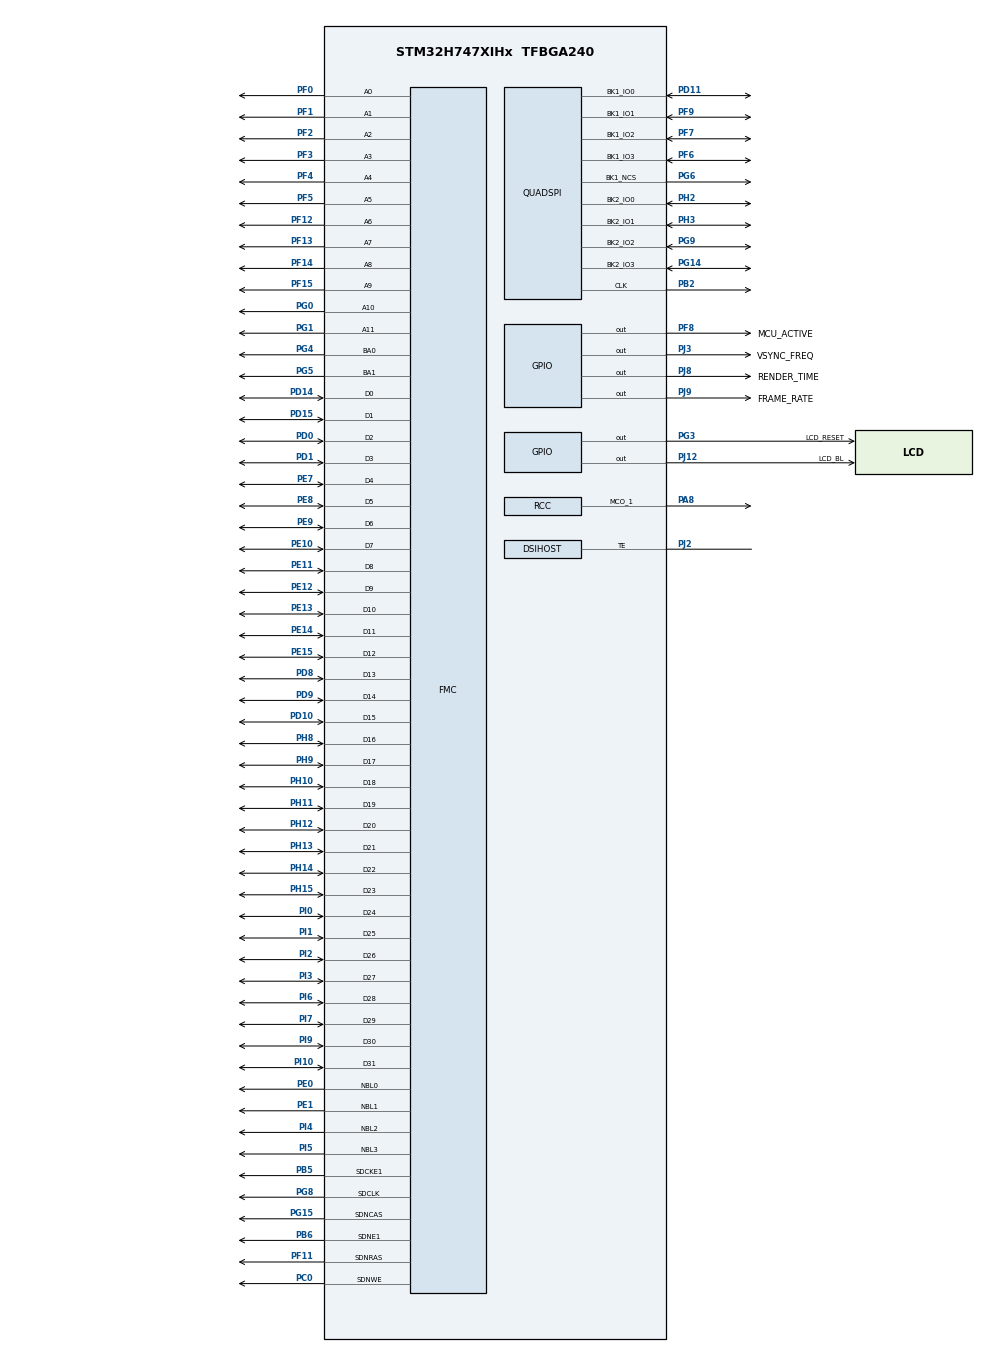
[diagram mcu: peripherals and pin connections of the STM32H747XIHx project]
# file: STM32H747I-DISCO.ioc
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CORTEX_M7.AccessPermission-Cortex_Memory_Protection_Unit_Region0_Settings=MPU_REGION_FULL_ACCESS
CORTEX_M7.AccessPermission-Cortex_Memory_Protection_Unit_Region1_Settings=MPU_REGION_FULL_ACCESS
CORTEX_M7.AccessPermission-Cortex_Memory_Protection_Unit_Region2_Settings=MPU_REGION_FULL_ACCESS
CORTEX_M7.AccessPermission-Cortex_Memory_Protection_Unit_Region3_Settings=MPU_REGION_FULL_ACCESS
CORTEX_M7.AccessPermission-Cortex_Memory_Protection_Unit_Region4_Settings=MPU_REGION_FULL_ACCESS
CORTEX_M7.AccessPermission-Cortex_Memory_Protection_Unit_Region5_Settings=MPU_REGION_FULL_ACCESS
CORTEX_M7.BaseAddress-Cortex_Memory_Protection_Unit_Region0_Settings=0x90000000
CORTEX_M7.BaseAddress-Cortex_Memory_Protection_Unit_Region1_Settings=0x90000000
CORTEX_M7.BaseAddress-Cortex_Memory_Protection_Unit_Region2_Settings=0xD0000000
CORTEX_M7.BaseAddress-Cortex_Memory_Protection_Unit_Region3_Settings=0x24000000
CORTEX_M7.BaseAddress-Cortex_Memory_Protection_Unit_Region4_Settings=0x10000000
CORTEX_M7.BaseAddress-Cortex_Memory_Protection_Unit_Region5_Settings=0x10040000
CORTEX_M7.CPU_DCache=Enabled
CORTEX_M7.CPU_ICache=Enabled
CORTEX_M7.DisableExec-Cortex_Memory_Protection_Unit_Region0_Settings=MPU_INSTRUCTION_ACCESS_DISABLE
CORTEX_M7.DisableExec-Cortex_Memory_Protection_Unit_Region1_Settings=MPU_INSTRUCTION_ACCESS_DISABLE
CORTEX_M7.DisableExec-Cortex_Memory_Protection_Unit_Region2_Settings=MPU_INSTRUCTION_ACCESS_DISABLE
CORTEX_M7.DisableExec-Cortex_Memory_Protection_Unit_Region3_Settings=MPU_INSTRUCTION_ACCESS_ENABLE
CORTEX_M7.DisableExec-Cortex_Memory_Protection_Unit_Region5_Settings=MPU_INSTRUCTION_ACCESS_DISABLE
CORTEX_M7.Enable-Cortex_Memory_Protection_Unit_Region0_Settings=MPU_REGION_ENABLE
CORTEX_M7.Enable-Cortex_Memory_Protection_Unit_Region1_Settings=MPU_REGION_ENABLE
CORTEX_M7.Enable-Cortex_Memory_Protection_Unit_Region2_Settings=MPU_REGION_ENABLE
CORTEX_M7.Enable-Cortex_Memory_Protection_Unit_Region3_Settings=MPU_REGION_ENABLE
CORTEX_M7.Enable-Cortex_Memory_Protection_Unit_Region4_Settings=MPU_REGION_ENABLE
CORTEX_M7.Enable-Cortex_Memory_Protection_Unit_Region5_Settings=MPU_REGION_ENABLE
CORTEX_M7.IsCacheable-Cortex_Memory_Protection_Unit_Region2_Settings=MPU_ACCESS_CACHEABLE
CORTEX_M7.IsCacheable-Cortex_Memory_Protection_Unit_Region3_Settings=MPU_ACCESS_CACHEABLE
CORTEX_M7.IsCacheable-Cortex_Memory_Protection_Unit_Region4_Settings=MPU_ACCESS_CACHEABLE
CORTEX_M7.IsCacheable-Cortex_Memory_Protection_Unit_Region5_Settings=MPU_ACCESS_CACHEABLE
CORTEX_M7.MPU_Control=MPU_PRIVILEGED_DEFAULT
CORTEX_M7.Size-Cortex_Memory_Protection_Unit_Region0_Settings=MPU_REGION_SIZE_256MB
CORTEX_M7.Size-Cortex_Memory_Protection_Unit_Region1_Settings=MPU_REGION_SIZE_128MB
CORTEX_M7.Size-Cortex_Memory_Protection_Unit_Region2_Settings=MPU_REGION_SIZE_32MB
CORTEX_M7.Size-Cortex_Memory_Protection_Unit_Region3_Settings=MPU_REGION_SIZE_512KB
CORTEX_M7.Size-Cortex_Memory_Protection_Unit_Region4_Settings=MPU_REGION_SIZE_256KB
CORTEX_M7.Size-Cortex_Memory_Protection_Unit_Region5_Settings=MPU_REGION_SIZE_32KB
CortexM4.IPs=CORTEX_M4\:I,DEBUG,FATFS_M4\:I,FREERTOS_M4\:I,IWDG2\:I,OPENAMP_M4\:I,PDM2PCM_M4\:I,PWR,RCC,RESMGR_UTILITY,SYS_M4\:I,USB_DEVICE_M4\:I,USB_HOST_M4\:I,VREFBUF,WWDG2\:I,DMA,BDMA,MDMA,NVIC2\:I,GPIO,STMicroelectronics.X-CUBE-AI.10.2.1_M4\:I
CortexM7.IPs=CORTEX_M7\:I,DEBUG\:I,FATFS_M7\:I,FREERTOS_M7\:I,IWDG1\:I,OPENAMP_M7\:I,PDM2PCM_M7\:I,PWR\:I,RCC\:I,RESMGR_UTILITY\:I,SYS\:I,USB_DEVICE_M7\:I,USB_HOST_M7\:I,VREFBUF\:I,WWDG1\:I,DMA\:I,BDMA\:I,MDMA\:I,NVIC1\:I,FMC\:I,QUADSPI\:I,DMA2D\:I,DSIHOST\:I,LTDC\:I,CRC\:I,TIM6\:I,GPIO\:I,JPEG\:I,LIBJPEG\:I
CortexM7.Pins=PJ12,PG3,PF8,PJ9,PJ8,PJ3
DMA2D.ColorMode=DMA2D_OUTPUT_RGB888
DMA2D.Mode=DMA2D_R2M
DSIHOST.AcknowledgeRequest=DSI_ACKNOWLEDGE_ENABLE
DSIHOST.AutomaticClockLaneControl=DSI_AUTO_CLK_LANE_CTRL_DISABLE
DSIHOST.AutomaticRefresh=DSI_AR_DISABLE
DSIHOST.CommandSize=400
DSIHOST.LPDcsLongWrite=DSI_LP_DLW_ENABLE
DSIHOST.LPDcsShortReadNoP=DSI_LP_DSR0P_ENABLE
DSIHOST.LPDcsShortWriteNoP=DSI_LP_DSW0P_ENABLE
DSIHOST.LPDcsShortWriteOneP=DSI_LP_DSW1P_ENABLE
DSIHOST.LPGenLongWrite=DSI_LP_GLW_ENABLE
DSIHOST.LPGenShortReadNoP=DSI_LP_GSR0P_ENABLE
DSIHOST.LPGenShortReadOneP=DSI_LP_GSR1P_ENABLE
DSIHOST.LPGenShortReadTwoP=DSI_LP_GSR2P_ENABLE
DSIHOST.LPGenShortWriteNoP=DSI_LP_GSW0P_ENABLE
DSIHOST.LPGenShortWriteOneP=DSI_LP_GSW1P_ENABLE
DSIHOST.LPGenShortWriteTwoP=DSI_LP_GSW2P_ENABLE
DSIHOST.LPMaxReadPacket=DSI_LP_MRDP_ENABLE
DSIHOST.LPWREIE=HAL_DSI_ERROR_NONE
DSIHOST.NumberOfLanes=DSI_TWO_DATA_LANES
DSIHOST.TEAcknowledgeRequest=DSI_TE_ACKNOWLEDGE_ENABLE
DSIHOST.TearingEffectPolarity=DSI_TE_RISING_EDGE
DSIHOST.TearingEffectSource=DSI_TE_EXTERNAL
DSIHOST.TimingPHY_TCLK_POST_Enable=__NULL
DSI_CKN.Mode=DSIHost_Adapted_TE
DSI_CKN.PinAttribute=CortexM7
DSI_CKN.Signal=DSIHOST_CKN
DSI_CKP.Mode=DSIHost_Adapted_TE
DSI_CKP.PinAttribute=CortexM7
DSI_CKP.Signal=DSIHOST_CKP
DSI_D0N.Mode=DSIHost_Adapted_TE
DSI_D0N.PinAttribute=CortexM7
DSI_D0N.Signal=DSIHOST_D0N
DSI_D0P.Mode=DSIHost_Adapted_TE
DSI_D0P.PinAttribute=CortexM7
DSI_D0P.Signal=DSIHOST_D0P
DSI_D1N.Mode=DSIHost_Adapted_TE
DSI_D1N.PinAttribute=CortexM7
DSI_D1N.Signal=DSIHOST_D1N
DSI_D1P.Mode=DSIHost_Adapted_TE
DSI_D1P.PinAttribute=CortexM7
DSI_D1P.Signal=DSIHOST_D1P
FMC.CASLatency1=FMC_SDRAM_CAS_LATENCY_3
FMC.ColumnBitsNumber1=FMC_SDRAM_COLUMN_BITS_NUM_9
FMC.ExitSelfRefreshDelay1=7
FMC.LoadToActiveDelay1=2
FMC.RCDDelay1=2
FMC.RPDelay1=2
FMC.ReadBurst1=FMC_SDRAM_RBURST_ENABLE
FMC.RowCycleDelay1=7
FMC.SDClockPeriod1=FMC_SDRAM_CLOCK_PERIOD_2
FMC.SDClockPeriod2=FMC_SDRAM_CLOCK_PERIOD_2
FMC.SelfRefreshTime1=4
FMC.WriteRecoveryTime1=3
FREERTOS_M7.Tasks01=TouchGFXTask,24,3048,TouchGFX_Task,As weak,NULL,Dynamic,NULL,NULL;videoTask,8,1000,videoTaskFunc,As external,NULL,Dynamic,NULL,NULL
FREERTOS_M7.configIDLE_SHOULD_YIELD=1
FREERTOS_M7.configTOTAL_HEAP_SIZE=100000
FREERTOS_M7.configUSE_APPLICATION_TASK_TAG=1
FREERTOS_M7.configUSE_IDLE_HOOK=1
JPEG.JPEG_RGB_FORMAT=JPEG_RGB888
LTDC.ActiveW=400
LTDC.Alpha0_L0=0
LTDC.Alpha_L0=255
LTDC.BlendingFactor1_L0=LTDC_BLENDING_FACTOR1_PAxCA
LTDC.BlendingFactor2_L0=LTDC_BLENDING_FACTOR2_PAxCA
LTDC.FBStartAdress_L0=0xD0000000
LTDC.HBP=2
LTDC.HFP=1
LTDC.HSPolarity=LTDC_HSPOLARITY_AH
LTDC.HSync=1
LTDC.ImageHeight_L0=480
LTDC.ImageWidth_L0=400
LTDC.Layers=0
LTDC.PixelFormat_L0=LTDC_PIXEL_FORMAT_RGB888
LTDC.VBP=2
LTDC.VFP=1
LTDC.VSPolarity=LTDC_VSPOLARITY_AH
LTDC.VSync=1
LTDC.WindowX1_L0=400
LTDC.WindowY1_L0=480
Mcu.Family=STM32H7
Mcu.Name=STM32H747XIHx
Mcu.Package=TFBGA240
Mdma.MDMA_Channel6.JPEG_OUTFIFO_TH.0.BlockCount=0
Mdma.MDMA_Channel6.JPEG_OUTFIFO_TH.0.BlockDataLength=0
Mdma.MDMA_Channel6.JPEG_OUTFIFO_TH.0.BufferTransferLength=32
Mdma.MDMA_Channel6.JPEG_OUTFIFO_TH.0.CircularMode=MDMA_LINEAR_LIST
Mdma.MDMA_Channel6.JPEG_OUTFIFO_TH.0.DataAlignment=MDMA_DATAALIGN_PACKENABLE
Mdma.MDMA_Channel6.JPEG_OUTFIFO_TH.0.DestBlockAddressOffset=0
Mdma.MDMA_Channel6.JPEG_OUTFIFO_TH.0.DestBurst=MDMA_DEST_BURST_32BEATS
Mdma.MDMA_Channel6.JPEG_OUTFIFO_TH.0.DestDataSize=MDMA_DEST_DATASIZE_BYTE
Mdma.MDMA_Channel6.JPEG_OUTFIFO_TH.0.DestinationInc=MDMA_DEST_INC_BYTE
Mdma.MDMA_Channel6.JPEG_OUTFIFO_TH.0.DstAddress=0
Mdma.MDMA_Channel6.JPEG_OUTFIFO_TH.0.Endianness=MDMA_LITTLE_ENDIANNESS_PRESERVE
Mdma.MDMA_Channel6.JPEG_OUTFIFO_TH.0.Instance=MDMA_Channel6
Mdma.MDMA_Channel6.JPEG_OUTFIFO_TH.0.MaskAddress=0
Mdma.MDMA_Channel6.JPEG_OUTFIFO_TH.0.MaskData=0
Mdma.MDMA_Channel6.JPEG_OUTFIFO_TH.0.Priority=MDMA_PRIORITY_VERY_HIGH
Mdma.MDMA_Channel6.JPEG_OUTFIFO_TH.0.Rank=First
Mdma.MDMA_Channel6.JPEG_OUTFIFO_TH.0.SourceBlockAddressOffset=0
Mdma.MDMA_Channel6.JPEG_OUTFIFO_TH.0.SourceBurst=MDMA_SOURCE_BURST_32BEATS
Mdma.MDMA_Channel6.JPEG_OUTFIFO_TH.0.SourceDataSize=MDMA_SRC_DATASIZE_WORD
Mdma.MDMA_Channel6.JPEG_OUTFIFO_TH.0.SourceInc=MDMA_SRC_INC_DISABLE
Mdma.MDMA_Channel6.JPEG_OUTFIFO_TH.0.SrcAddress=0
Mdma.MDMA_Channel6.JPEG_OUTFIFO_TH.0.TransferTriggerMode=MDMA_BUFFER_TRANSFER
Mdma.MDMA_Channel6.Request0=JPEG_OUTFIFO_TH
Mdma.MDMA_Channel6.RequestsNb=1
Mdma.MDMA_Channel7.JPEG_INFIFO_TH.0.BlockCount=0
Mdma.MDMA_Channel7.JPEG_INFIFO_TH.0.BlockDataLength=0
Mdma.MDMA_Channel7.JPEG_INFIFO_TH.0.BufferTransferLength=32
Mdma.MDMA_Channel7.JPEG_INFIFO_TH.0.CircularMode=MDMA_LINEAR_LIST
Mdma.MDMA_Channel7.JPEG_INFIFO_TH.0.DataAlignment=MDMA_DATAALIGN_PACKENABLE
Mdma.MDMA_Channel7.JPEG_INFIFO_TH.0.DestBlockAddressOffset=0
Mdma.MDMA_Channel7.JPEG_INFIFO_TH.0.DestBurst=MDMA_DEST_BURST_16BEATS
Mdma.MDMA_Channel7.JPEG_INFIFO_TH.0.DestDataSize=MDMA_DEST_DATASIZE_WORD
Mdma.MDMA_Channel7.JPEG_INFIFO_TH.0.DestinationInc=MDMA_DEST_INC_DISABLE
Mdma.MDMA_Channel7.JPEG_INFIFO_TH.0.DstAddress=0
Mdma.MDMA_Channel7.JPEG_INFIFO_TH.0.Endianness=MDMA_LITTLE_ENDIANNESS_PRESERVE
Mdma.MDMA_Channel7.JPEG_INFIFO_TH.0.Instance=MDMA_Channel7
Mdma.MDMA_Channel7.JPEG_INFIFO_TH.0.MaskAddress=0
Mdma.MDMA_Channel7.JPEG_INFIFO_TH.0.MaskData=0
Mdma.MDMA_Channel7.JPEG_INFIFO_TH.0.Priority=MDMA_PRIORITY_HIGH
Mdma.MDMA_Channel7.JPEG_INFIFO_TH.0.Rank=First
Mdma.MDMA_Channel7.JPEG_INFIFO_TH.0.SourceBlockAddressOffset=0
Mdma.MDMA_Channel7.JPEG_INFIFO_TH.0.SourceBurst=MDMA_SOURCE_BURST_32BEATS
Mdma.MDMA_Channel7.JPEG_INFIFO_TH.0.SourceDataSize=MDMA_SRC_DATASIZE_BYTE
Mdma.MDMA_Channel7.JPEG_INFIFO_TH.0.SourceInc=MDMA_SRC_INC_BYTE
Mdma.MDMA_Channel7.JPEG_INFIFO_TH.0.SrcAddress=0
Mdma.MDMA_Channel7.JPEG_INFIFO_TH.0.TransferTriggerMode=MDMA_BUFFER_TRANSFER
Mdma.MDMA_Channel7.Request0=JPEG_INFIFO_TH
Mdma.MDMA_Channel7.RequestsNb=1
Mdma.RequestSet0=MDMA_Channel7
Mdma.RequestSet1=MDMA_Channel6
Mdma.RequestSetsNb=2
NVIC1.DMA2D_IRQn=true\:7\:0\:true\:false\:true\:true\:true\:true\:true
NVIC1.DSI_IRQn=true\:7\:0\:true\:false\:true\:true\:true\:true\:true
NVIC1.JPEG_IRQn=true\:5\:0\:false\:false\:true\:true\:true\:true\:true
NVIC1.LTDC_IRQn=true\:7\:0\:true\:false\:true\:true\:true\:true\:true
NVIC1.MDMA_IRQn=true\:5\:0\:false\:false\:true\:true\:false\:true\:true
NVIC1.PriorityGroup=NVIC_PRIORITYGROUP_4
NVIC1.TIM6_DAC_IRQn=true\:0\:0\:false\:false\:true\:false\:false\:true\:true
NVIC1.TimeBase=TIM6_DAC_IRQn
NVIC1.TimeBaseIP=TIM6
NVIC2.PriorityGroup=NVIC_PRIORITYGROUP_4
PA8.Mode=Clock-out-1
PA8.PinAttribute=CortexM7
PA8.Signal=RCC_MCO_1
PB2.Mode=Dual_Bank
PB2.PinAttribute=CortexM7
PB2.Signal=QUADSPI_CLK
PB5.Mode=SdramChipSelect2_1
PB5.PinAttribute=CortexM7
PB5.Signal=FMC_SDCKE1
PB6.Mode=SdramChipSelect2_1
PB6.PinAttribute=CortexM7
PB6.Signal=FMC_SDNE1
PC0.PinAttribute=CortexM7
PC0.Signal=FMC_SDNWE
PC14-OSC32_IN\ (OSC32_IN).Mode=LSE-External-Oscillator
PC14-OSC32_IN\ (OSC32_IN).PinAttribute=CortexM7
PC14-OSC32_IN\ (OSC32_IN).Signal=RCC_OSC32_IN
PC15-OSC32_OUT\ (OSC32_OUT).Mode=LSE-External-Oscillator
PC15-OSC32_OUT\ (OSC32_OUT).PinAttribute=CortexM7
PC15-OSC32_OUT\ (OSC32_OUT).Signal=RCC_OSC32_OUT
PD0.PinAttribute=CortexM7
PD0.Signal=FMC_D2_DA2
PD1.PinAttribute=CortexM7
PD1.Signal=FMC_D3_DA3
PD10.PinAttribute=CortexM7
PD10.Signal=FMC_D15_DA15
PD11.Mode=Dual_Bank
PD11.PinAttribute=CortexM7
PD11.Signal=QUADSPI_BK1_IO0
PD14.PinAttribute=CortexM7
PD14.Signal=FMC_D0_DA0
PD15.PinAttribute=CortexM7
PD15.Signal=FMC_D1_DA1
PD8.PinAttribute=CortexM7
PD8.Signal=FMC_D13_DA13
PD9.PinAttribute=CortexM7
PD9.Signal=FMC_D14_DA14
PE0.PinAttribute=CortexM7
PE0.Signal=FMC_NBL0
PE1.PinAttribute=CortexM7
PE1.Signal=FMC_NBL1
PE10.PinAttribute=CortexM7
PE10.Signal=FMC_D7_DA7
PE11.PinAttribute=CortexM7
PE11.Signal=FMC_D8_DA8
PE12.PinAttribute=CortexM7
PE12.Signal=FMC_D9_DA9
PE13.PinAttribute=CortexM7
PE13.Signal=FMC_D10_DA10
PE14.PinAttribute=CortexM7
PE14.Signal=FMC_D11_DA11
PE15.PinAttribute=CortexM7
PE15.Signal=FMC_D12_DA12
PE7.PinAttribute=CortexM7
PE7.Signal=FMC_D4_DA4
PE8.PinAttribute=CortexM7
PE8.Signal=FMC_D5_DA5
PE9.PinAttribute=CortexM7
PE9.Signal=FMC_D6_DA6
PF0.PinAttribute=CortexM7
PF0.Signal=FMC_A0
PF1.PinAttribute=CortexM7
PF1.Signal=FMC_A1
PF11.PinAttribute=CortexM7
PF11.Signal=FMC_SDNRAS
PF12.PinAttribute=CortexM7
PF12.Signal=FMC_A6
PF13.PinAttribute=CortexM7
PF13.Signal=FMC_A7
PF14.PinAttribute=CortexM7
PF14.Signal=FMC_A8
PF15.PinAttribute=CortexM7
PF15.Signal=FMC_A9
PF2.PinAttribute=CortexM7
PF2.Signal=FMC_A2
PF3.PinAttribute=CortexM7
PF3.Signal=FMC_A3
PF4.PinAttribute=CortexM7
PF4.Signal=FMC_A4
PF5.PinAttribute=CortexM7
PF5.Signal=FMC_A5
PF6.Mode=Dual_Bank
PF6.PinAttribute=CortexM7
PF6.Signal=QUADSPI_BK1_IO3
PF7.Mode=Dual_Bank
PF7.PinAttribute=CortexM7
PF7.Signal=QUADSPI_BK1_IO2
PF8.GPIO_Label=MCU_ACTIVE
PF8.GPIO_Speed=GPIO_SPEED_FREQ_VERY_HIGH
PF8.PinAttribute=CortexM7
PF8.Signal=GPIO_Output
PF9.Mode=Dual_Bank
PF9.PinAttribute=CortexM7
PF9.Signal=QUADSPI_BK1_IO1
PG0.PinAttribute=CortexM7
PG0.Signal=FMC_A10
PG1.PinAttribute=CortexM7
PG1.Signal=FMC_A11
PG14.Mode=Dual_Bank
PG14.PinAttribute=CortexM7
PG14.Signal=QUADSPI_BK2_IO3
PG15.PinAttribute=CortexM7
PG15.Signal=FMC_SDNCAS
PG3.GPIO_Label=LCD_RESET
PG3.GPIO_PuPd=GPIO_PULLUP
PG3.GPIO_Speed=GPIO_SPEED_FREQ_VERY_HIGH
PG3.PinAttribute=CortexM7
PG3.Signal=GPIO_Output
PG4.PinAttribute=CortexM7
PG4.Signal=FMC_A14_BA0
PG5.PinAttribute=CortexM7
PG5.Signal=FMC_A15_BA1
PG6.Mode=Enable Chip Select 1 for both banks
PG6.PinAttribute=CortexM7
PG6.Signal=QUADSPI_BK1_NCS
PG8.PinAttribute=CortexM7
PG8.Signal=FMC_SDCLK
PG9.Mode=Dual_Bank
PG9.PinAttribute=CortexM7
PG9.Signal=QUADSPI_BK2_IO2
PH0-OSC_IN\ (PH0).Mode=HSE-External-Clock-Source
PH0-OSC_IN\ (PH0).PinAttribute=CortexM7
PH0-OSC_IN\ (PH0).Signal=RCC_OSC_IN
PH10.PinAttribute=CortexM7
PH10.Signal=FMC_D18
PH11.PinAttribute=CortexM7
PH11.Signal=FMC_D19
PH12.PinAttribute=CortexM7
PH12.Signal=FMC_D20
PH13.PinAttribute=CortexM7
PH13.Signal=FMC_D21
PH14.PinAttribute=CortexM7
PH14.Signal=FMC_D22
PH15.PinAttribute=CortexM7
PH15.Signal=FMC_D23
PH2.Mode=Dual_Bank
PH2.PinAttribute=CortexM7
PH2.Signal=QUADSPI_BK2_IO0
PH3.Mode=Dual_Bank
PH3.PinAttribute=CortexM7
PH3.Signal=QUADSPI_BK2_IO1
PH8.PinAttribute=CortexM7
PH8.Signal=FMC_D16
PH9.PinAttribute=CortexM7
PH9.Signal=FMC_D17
PI0.PinAttribute=CortexM7
PI0.Signal=FMC_D24
PI1.PinAttribute=CortexM7
PI1.Signal=FMC_D25
PI10.PinAttribute=CortexM7
PI10.Signal=FMC_D31
PI2.PinAttribute=CortexM7
PI2.Signal=FMC_D26
PI3.PinAttribute=CortexM7
PI3.Signal=FMC_D27
PI4.PinAttribute=CortexM7
PI4.Signal=FMC_NBL2
PI5.PinAttribute=CortexM7
PI5.Signal=FMC_NBL3
PI6.PinAttribute=CortexM7
PI6.Signal=FMC_D28
PI7.PinAttribute=CortexM7
PI7.Signal=FMC_D29
PI9.PinAttribute=CortexM7
PI9.Signal=FMC_D30
PJ12.GPIO_Label=LCD_BL
PJ12.GPIO_Speed=GPIO_SPEED_FREQ_VERY_HIGH
PJ12.PinAttribute=CortexM7
PJ12.Signal=GPIO_Output
PJ2.Mode=DSIHost_Adapted_TE
PJ2.PinAttribute=CortexM7
PJ2.Signal=DSIHOST_TE
PJ3.GPIO_Label=VSYNC_FREQ
PJ3.GPIO_Speed=GPIO_SPEED_FREQ_VERY_HIGH
PJ3.PinAttribute=CortexM7
PJ3.Signal=GPIO_Output
PJ8.GPIO_Label=RENDER_TIME
PJ8.GPIO_Speed=GPIO_SPEED_FREQ_VERY_HIGH
PJ8.PinAttribute=CortexM7
PJ8.Signal=GPIO_Output
PJ9.GPIO_Label=FRAME_RATE
PJ9.GPIO_Speed=GPIO_SPEED_FREQ_VERY_HIGH
PJ9.PinAttribute=CortexM7
PJ9.Signal=GPIO_Output
ProjectManager.HeapSize=M4-0x1000,M7-0x1000
ProjectManager.StackSize=M4-0x1000,M7-0x1000
ProjectManager.TargetToolchain=STM32CubeIDE
QUADSPI.ClockPrescaler=3
RCC.ADCFreq_Value=16125000
RCC.APB1CLKDivider=RCC_HCLK_DIV4
RCC.APB1Freq_Value=120000000
RCC.APB2CLKDivider=RCC_HCLK_DIV2
RCC.APB2Freq_Value=120000000
RCC.APB3Freq_Value=120000000
RCC.APB4Freq_Value=120000000
RCC.CortexFreq_Value=480000000
RCC.D1PPRE=RCC_APB3_DIV2
RCC.D2PPRE1=RCC_APB1_DIV2
RCC.D2PPRE2=RCC_APB2_DIV2
RCC.D3PPRE=RCC_APB4_DIV2
RCC.DIVM1=4
RCC.DIVM3=4
RCC.DIVN1=480
RCC.DIVN3=480
RCC.DIVQ1=20
RCC.DIVQ3=8
RCC.DIVR3=21
RCC.FLatency=FLASH_LATENCY_4
RCC.HCLKFreq_Value=240000000
RCC.HPRE=RCC_HCLK_DIV2
RCC.HSE_VALUE=8000000
RCC.PLL2FRACN=0
RCC.PLL3FRACN=0
RCC.PLLDSIIDF=DSI_PLL_IN_DIV3
RCC.PLLDSINDIV=119
RCC.PLLDSIODF=DSI_PLL_OUT_DIV2
RCC.PLLFRACN=0
RCC.PLLM=25
RCC.PLLMUL=RCC_PLL_MUL9
RCC.PLLN=432
RCC.PLLQ=9
RCC.PLLSourceVirtual=RCC_PLLSOURCE_HSE
RCC.PRESCALERUSB=RCC_USBCLKSOURCE_PLL_DIV1_5
RCC.PWR_Regulator_Voltage_Scale=PWR_REGULATOR_VOLTAGE_SCALE0
RCC.SYSCLKFreq_VALUE=480000000
RCC.SYSCLKSource=RCC_SYSCLKSOURCE_PLLCLK
RCC.SYSCLKSourceVirtual=RCC_SYSCLKSOURCE_PLLCLK
RCC.USBFreq_Value=48000000
SH.FMC_A0.0=FMC_A0,12b-sda1
SH.FMC_A1.0=FMC_A1,12b-sda1
SH.FMC_A10.0=FMC_A10,12b-sda1
SH.FMC_A11.0=FMC_A11,12b-sda1
SH.FMC_A14_BA0.0=FMC_BA0,FourSdramBanks1
SH.FMC_A15_BA1.0=FMC_BA1,FourSdramBanks1
SH.FMC_A2.0=FMC_A2,12b-sda1
SH.FMC_A3.0=FMC_A3,12b-sda1
SH.FMC_A4.0=FMC_A4,12b-sda1
SH.FMC_A5.0=FMC_A5,12b-sda1
SH.FMC_A6.0=FMC_A6,12b-sda1
SH.FMC_A7.0=FMC_A7,12b-sda1
SH.FMC_A8.0=FMC_A8,12b-sda1
SH.FMC_A9.0=FMC_A9,12b-sda1
SH.FMC_D0_DA0.0=FMC_D0,sd-32b-d1
SH.FMC_D10_DA10.0=FMC_D10,sd-32b-d1
SH.FMC_D11_DA11.0=FMC_D11,sd-32b-d1
SH.FMC_D12_DA12.0=FMC_D12,sd-32b-d1
SH.FMC_D13_DA13.0=FMC_D13,sd-32b-d1
SH.FMC_D14_DA14.0=FMC_D14,sd-32b-d1
SH.FMC_D15_DA15.0=FMC_D15,sd-32b-d1
SH.FMC_D16.0=FMC_D16,sd-32b-d1
SH.FMC_D17.0=FMC_D17,sd-32b-d1
SH.FMC_D18.0=FMC_D18,sd-32b-d1
SH.FMC_D19.0=FMC_D19,sd-32b-d1
SH.FMC_D1_DA1.0=FMC_D1,sd-32b-d1
SH.FMC_D20.0=FMC_D20,sd-32b-d1
SH.FMC_D21.0=FMC_D21,sd-32b-d1
SH.FMC_D22.0=FMC_D22,sd-32b-d1
SH.FMC_D23.0=FMC_D23,sd-32b-d1
SH.FMC_D24.0=FMC_D24,sd-32b-d1
SH.FMC_D25.0=FMC_D25,sd-32b-d1
SH.FMC_D26.0=FMC_D26,sd-32b-d1
SH.FMC_D27.0=FMC_D27,sd-32b-d1
SH.FMC_D28.0=FMC_D28,sd-32b-d1
SH.FMC_D29.0=FMC_D29,sd-32b-d1
SH.FMC_D2_DA2.0=FMC_D2,sd-32b-d1
SH.FMC_D30.0=FMC_D30,sd-32b-d1
SH.FMC_D31.0=FMC_D31,sd-32b-d1
SH.FMC_D3_DA3.0=FMC_D3,sd-32b-d1
SH.FMC_D4_DA4.0=FMC_D4,sd-32b-d1
SH.FMC_D5_DA5.0=FMC_D5,sd-32b-d1
SH.FMC_D6_DA6.0=FMC_D6,sd-32b-d1
SH.FMC_D7_DA7.0=FMC_D7,sd-32b-d1
SH.FMC_D8_DA8.0=FMC_D8,sd-32b-d1
SH.FMC_D9_DA9.0=FMC_D9,sd-32b-d1
SH.FMC_NBL0.0=FMC_NBL0,Sd4ByteEnable1
SH.FMC_NBL1.0=FMC_NBL1,Sd4ByteEnable1
SH.FMC_NBL2.0=FMC_NBL2,Sd4ByteEnable1
SH.FMC_NBL3.0=FMC_NBL3,Sd4ByteEnable1
SH.FMC_SDCLK.0=FMC_SDCLK,12b-sda1
SH.FMC_SDNCAS.0=FMC_SDNCAS,12b-sda1
SH.FMC_SDNRAS.0=FMC_SDNRAS,12b-sda1
SH.FMC_SDNWE.0=FMC_SDNWE,12b-sda1
STMicroelectronics.X-CUBE-AI.10.2.1_M4.HeapSize=0x1000
STMicroelectronics.X-CUBE-AI.10.2.1_M4.LatestDirectoryUsed-ef50f1e0dc524e4307271b973ba9a3fdd50908a36a1dbe44ed89bcef48880d24=C\:\\Users\\ironpc\\OneDrive\\Desktop\\st project\\TinyML_CAN_IDS
STMicroelectronics.X-CUBE-AI.10.2.1_M4.ModelActualCompression-ef50f1e0dc524e4307271b973ba9a3fdd50908a36a1dbe44ed89bcef48880d24=0.0
STMicroelectronics.X-CUBE-AI.10.2.1_M4.ModelCompression-ef50f1e0dc524e4307271b973ba9a3fdd50908a36a1dbe44ed89bcef48880d24=None
STMicroelectronics.X-CUBE-AI.10.2.1_M4.ModelFlashOccupation-ef50f1e0dc524e4307271b973ba9a3fdd50908a36a1dbe44ed89bcef48880d24=1092
STMicroelectronics.X-CUBE-AI.10.2.1_M4.ModelHashList=ef50f1e0dc524e4307271b973ba9a3fdd50908a36a1dbe44ed89bcef48880d24
STMicroelectronics.X-CUBE-AI.10.2.1_M4.ModelKind-ef50f1e0dc524e4307271b973ba9a3fdd50908a36a1dbe44ed89bcef48880d24=ONNX
STMicroelectronics.X-CUBE-AI.10.2.1_M4.ModelMacc-ef50f1e0dc524e4307271b973ba9a3fdd50908a36a1dbe44ed89bcef48880d24=362
STMicroelectronics.X-CUBE-AI.10.2.1_M4.ModelName-ef50f1e0dc524e4307271b973ba9a3fdd50908a36a1dbe44ed89bcef48880d24=can_ids_model
STMicroelectronics.X-CUBE-AI.10.2.1_M4.ModelNameList=can_ids_model
STMicroelectronics.X-CUBE-AI.10.2.1_M4.ModelRamOccupation-ef50f1e0dc524e4307271b973ba9a3fdd50908a36a1dbe44ed89bcef48880d24=96
STMicroelectronics.X-CUBE-AI.10.2.1_M4.ModelStructureFile-ef50f1e0dc524e4307271b973ba9a3fdd50908a36a1dbe44ed89bcef48880d24=C\:\\Users\\ironpc\\OneDrive\\Desktop\\st project\\TinyML_CAN_IDS\\can_ids_model.onnx
STMicroelectronics.X-CUBE-AI.10.2.1_M4.StackSize=0x1000
STMicroelectronics.X-CUBE-AI.10.2.1_M4.WorkingBufferStartAddrList=0xFFFFFFFF
STMicroelectronics.X-CUBE-AI.10.2.1_M4.XAaCUBEAaAICcArtificialOoIntelligenceJjCore=true
SYS.userName=SYS_M7
VP_CRC_VS_CRC.Mode=CRC_Activate
VP_DMA2D_VS_DMA2D.Mode=DMA2D_Activate
VP_FREERTOS_M7_VS_CMSIS_V2.Mode=CMSIS_V2
VP_JPEG_VS_JPEG.Mode=JPEG_Activate
VP_LIBJPEG_VS_JPEGLIB.Mode=Enabled
VP_LTDC_DSIMode.Mode=RGB888
VP_STMicroelectronics.X-CUBE-AI_M4_VS_ArtificialOoIntelligenceJjXAaCUBEAaAI_10.2.1.Mode=ArtificialOoIntelligenceJjXAaCUBEAaAI
VP_SYS_M4_VS_Systick.Mode=SysTick
VP_SYS_VS_tim6.Mode=TIM6
board=custom

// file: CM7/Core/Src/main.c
/* USER CODE BEGIN Header */
/**
  ******************************************************************************
  * @file           : main.c
  * @brief          : Main program body
  ******************************************************************************
  * @attention
  *
  * <h2><center>&copy; Copyright (c) 2021 STMicroelectronics.
  * All rights reserved.</center></h2>
  *
  * This software component is licensed by ST under Ultimate Liberty license
  * SLA0044, the "License"; You may not use this file except in compliance with
  * the License. You may obtain a copy of the License at:
  *                             www.st.com/SLA0044
  *
  ******************************************************************************
  */
/* USER CODE END Header */
#include "main.h"
#include "FreeRTOS.h"
#include "cmsis_os2.h"
#include "libjpeg.h"
#include "app_touchgfx.h"

/* USER CODE BEGIN PD */

#ifndef HSEM_ID_0
#define HSEM_ID_0 (0U) /* HW semaphore 0*/
#endif
/* USER CODE END PD */

CRC_HandleTypeDef hcrc;

DMA2D_HandleTypeDef hdma2d;

DSI_HandleTypeDef hdsi;

JPEG_HandleTypeDef hjpeg;
MDMA_HandleTypeDef hmdma_jpeg_infifo_th;
MDMA_HandleTypeDef hmdma_jpeg_outfifo_th;

LTDC_HandleTypeDef hltdc;

QSPI_HandleTypeDef hqspi;

SDRAM_HandleTypeDef hsdram1;

/* Definitions for TouchGFXTask */
osThreadId_t TouchGFXTaskHandle;
const osThreadAttr_t TouchGFXTask_attributes = {
  .name = "TouchGFXTask",
  .stack_size = 8192 * 4,
  .priority = (osPriority_t) osPriorityNormal,
};
/* Definitions for videoTask */
osThreadId_t videoTaskHandle;
const osThreadAttr_t videoTask_attributes = {
  .name = "videoTask",
  .stack_size = 1000 * 4,
  .priority = (osPriority_t) osPriorityLow,
};
/* USER CODE BEGIN PV */
OTM8009A_Object_t OTM8009AObj;
OTM8009A_IO_t IOCtx;
/* USER CODE END PV */

void SystemClock_Config(void);
static void MPU_Config(void);
static void MX_GPIO_Init(void);
static void MX_MDMA_Init(void);
static void MX_FMC_Init(void);
static void MX_QUADSPI_Init(void);
static void MX_DMA2D_Init(void);
static void MX_DSIHOST_DSI_Init(void);
static void MX_LTDC_Init(void);
static void MX_CRC_Init(void);
static void MX_JPEG_Init(void);
void TouchGFX_Task(void *argument);
extern void videoTaskFunc(void *argument);

int main(void)
{

/* USER CODE BEGIN Boot_Mode_Sequence_0 */
  int32_t timeout;
/* USER CODE END Boot_Mode_Sequence_0 */

  /* MPU Configuration--------------------------------------------------------*/
  MPU_Config();

  /* Enable the CPU Cache */

  /* Enable I-Cache---------------------------------------------------------*/
  SCB_EnableICache();

  /* Enable D-Cache---------------------------------------------------------*/
  SCB_EnableDCache();

/* USER CODE BEGIN Boot_Mode_Sequence_1 */
  /* Wait until CPU2 boots and enters in stop mode or timeout (non-blocking) */
  timeout = 0xFFFF;
  while((__HAL_RCC_GET_FLAG(RCC_FLAG_D2CKRDY) != RESET) && (timeout-- > 0));
/* USER CODE END Boot_Mode_Sequence_1 */
  /* MCU Configuration--------------------------------------------------------*/

  /* Reset of all peripherals, Initializes the Flash interface and the Systick. */
  HAL_Init();

  /* USER CODE BEGIN Init */
  /* Small delay to let CAN transceiver signals on PB8/PB9 stabilize
     before QSPI/FMC/DSI initialization (prevents black screen at reset) */
  HAL_Delay(200);
  /* OTA PERSISTENCE: Activer l'accès au domaine Backup AVANT TouchGFX */
  HAL_PWR_EnableBkUpAccess();
  /* USER CODE END Init */

  /* Configure the system clock */
  SystemClock_Config();
/* USER CODE BEGIN Boot_Mode_Sequence_2 */
/* [FDCAN CLK FIX] Enable FDCAN kernel clock (HSE) + peripheral clocks for BOTH CPU1 (CM7) and CPU2 (CM4) BEFORE releasing CM4 */
{
  RCC_PeriphCLKInitTypeDef fdcan_clk_init = {0};
  fdcan_clk_init.PeriphClockSelection = RCC_PERIPHCLK_FDCAN;
  fdcan_clk_init.FdcanClockSelection  = RCC_FDCANCLKSOURCE_HSE;
  if (HAL_RCCEx_PeriphCLKConfig(&fdcan_clk_init) != HAL_OK)
  {
    Error_Handler();
  }
  __HAL_RCC_FDCAN_CLK_ENABLE();     /* APB1HENR.FDCANEN  -> visible par CM7 */
  __HAL_RCC_C2_FDCAN_CLK_ENABLE();  /* C2APB1HENR.FDCANEN -> visible par CM4 */
  __HAL_RCC_GPIOA_CLK_ENABLE();     /* PA11/PA12 PMOD */
  __HAL_RCC_C2_GPIOA_CLK_ENABLE();  /* idem cote CM4 */
}
/* When system initialization is finished, Cortex-M7 will release Cortex-M4 by means of
HSEM notification */
/*HW semaphore Clock enable*/
__HAL_RCC_HSEM_CLK_ENABLE();
/*Take HSEM */
HAL_HSEM_FastTake(HSEM_ID_0);
/*Release HSEM in order to notify the CPU2(CM4)*/
HAL_HSEM_Release(HSEM_ID_0,0);
/* wait until CPU2 wakes up from stop mode (non-blocking) */
timeout = 0xFFFF;
while((__HAL_RCC_GET_FLAG(RCC_FLAG_D2CKRDY) == RESET) && (timeout-- > 0));
/* USER CODE END Boot_Mode_Sequence_2 */

  /* Initialize all configured peripherals */
  /* DEBUG: write boot progress to SRAM4+0x100 (0x38000100) */
  #define DBG_BOOT (*((volatile uint32_t*)0x38000100))
  DBG_BOOT = 0x01; MX_GPIO_Init();
  DBG_BOOT = 0x02; MX_MDMA_Init();
  DBG_BOOT = 0x03; MX_FMC_Init();
  DBG_BOOT = 0x04; MX_QUADSPI_Init();
  DBG_BOOT = 0x05; MX_DMA2D_Init();
  DBG_BOOT = 0x06; MX_DSIHOST_DSI_Init();
  DBG_BOOT = 0x07; MX_LTDC_Init();
  DBG_BOOT = 0x08; MX_CRC_Init();
  DBG_BOOT = 0x09; MX_JPEG_Init();
  DBG_BOOT = 0x0A; MX_LIBJPEG_Init();
  DBG_BOOT = 0x0B; MX_TouchGFX_Init();
  DBG_BOOT = 0x0C;
  /* Call PreOsInit function */
  MX_TouchGFX_PreOSInit();
  DBG_BOOT = 0x0D;

  /* Init scheduler */
  osKernelInitialize();

  /* Create the thread(s) */
  /* creation of TouchGFXTask */
  TouchGFXTaskHandle = osThreadNew(TouchGFX_Task, NULL, &TouchGFXTask_attributes);

  /* creation of videoTask */
  // videoTaskHandle = osThreadNew(videoTaskFunc, NULL, &videoTask_attributes);

  /* Start scheduler */
  osKernelStart();

  /* We should never get here as control is now taken by the scheduler */

  /* Infinite loop */
  while (1)
  {

  }
}

void SystemClock_Config(void)
{
  RCC_OscInitTypeDef RCC_OscInitStruct = {0};
  RCC_ClkInitTypeDef RCC_ClkInitStruct = {0};

  /** Supply configuration update enable
  */
  HAL_PWREx_ConfigSupply(PWR_DIRECT_SMPS_SUPPLY);

  /** Configure the main internal regulator output voltage
  */
  __HAL_PWR_VOLTAGESCALING_CONFIG(PWR_REGULATOR_VOLTAGE_SCALE1);

  while(!__HAL_PWR_GET_FLAG(PWR_FLAG_VOSRDY)) {}

  /** Initializes the RCC Oscillators according to the specified parameters
  * in the RCC_OscInitTypeDef structure.
  */
  RCC_OscInitStruct.OscillatorType = RCC_OSCILLATORTYPE_HSI|RCC_OSCILLATORTYPE_HSE;
  RCC_OscInitStruct.HSEState = RCC_HSE_ON;
  RCC_OscInitStruct.HSIState = RCC_HSI_DIV1;
  RCC_OscInitStruct.HSICalibrationValue = RCC_HSICALIBRATION_DEFAULT;
  RCC_OscInitStruct.PLL.PLLState = RCC_PLL_ON;
  RCC_OscInitStruct.PLL.PLLSource = RCC_PLLSOURCE_HSE;
  RCC_OscInitStruct.PLL.PLLM = 5;
  RCC_OscInitStruct.PLL.PLLN = 160;
  RCC_OscInitStruct.PLL.PLLP = 2;
  RCC_OscInitStruct.PLL.PLLQ = 2;
  RCC_OscInitStruct.PLL.PLLR = 2;
  RCC_OscInitStruct.PLL.PLLRGE = RCC_PLL1VCIRANGE_2;
  RCC_OscInitStruct.PLL.PLLVCOSEL = RCC_PLL1VCOWIDE;
  RCC_OscInitStruct.PLL.PLLFRACN = 0;
  if (HAL_RCC_OscConfig(&RCC_OscInitStruct) != HAL_OK)
  {
    Error_Handler();
  }

  /** Initializes the CPU, AHB and APB buses clocks
  */
  RCC_ClkInitStruct.ClockType = RCC_CLOCKTYPE_HCLK|RCC_CLOCKTYPE_SYSCLK
                              |RCC_CLOCKTYPE_PCLK1|RCC_CLOCKTYPE_PCLK2
                              |RCC_CLOCKTYPE_D3PCLK1|RCC_CLOCKTYPE_D1PCLK1;
  RCC_ClkInitStruct.SYSCLKSource = RCC_SYSCLKSOURCE_PLLCLK;
  RCC_ClkInitStruct.SYSCLKDivider = RCC_SYSCLK_DIV1;
  RCC_ClkInitStruct.AHBCLKDivider = RCC_HCLK_DIV2;
  RCC_ClkInitStruct.APB3CLKDivider = RCC_APB3_DIV2;
  RCC_ClkInitStruct.APB1CLKDivider = RCC_APB1_DIV2;
  RCC_ClkInitStruct.APB2CLKDivider = RCC_APB2_DIV2;
  RCC_ClkInitStruct.APB4CLKDivider = RCC_APB4_DIV2;

  if (HAL_RCC_ClockConfig(&RCC_ClkInitStruct, FLASH_LATENCY_2) != HAL_OK)
  {
    Error_Handler();
  }
  HAL_RCC_MCOConfig(RCC_MCO1, RCC_MCO1SOURCE_HSI, RCC_MCODIV_1);
}

static void MX_CRC_Init(void)
{

  hcrc.Instance = CRC;
  hcrc.Init.DefaultPolynomialUse = DEFAULT_POLYNOMIAL_ENABLE;
  hcrc.Init.DefaultInitValueUse = DEFAULT_INIT_VALUE_ENABLE;
  hcrc.Init.InputDataInversionMode = CRC_INPUTDATA_INVERSION_NONE;
  hcrc.Init.OutputDataInversionMode = CRC_OUTPUTDATA_INVERSION_DISABLE;
  hcrc.InputDataFormat = CRC_INPUTDATA_FORMAT_BYTES;
  if (HAL_CRC_Init(&hcrc) != HAL_OK)
  {
    Error_Handler();
  }

}

static void MX_DMA2D_Init(void)
{

  hdma2d.Instance = DMA2D;
  hdma2d.Init.Mode = DMA2D_R2M;
  hdma2d.Init.ColorMode = DMA2D_OUTPUT_RGB888;
  hdma2d.Init.OutputOffset = 0;
  if (HAL_DMA2D_Init(&hdma2d) != HAL_OK)
  {
    Error_Handler();
  }

}

static void MX_DSIHOST_DSI_Init(void)
{

  /* USER CODE BEGIN DSIHOST_Init 0 */
  HAL_GPIO_WritePin(GPIOG , GPIO_PIN_3 , GPIO_PIN_RESET);
  HAL_Delay(20);/* wait 20 ms */
  HAL_GPIO_WritePin(GPIOG , GPIO_PIN_3, GPIO_PIN_SET);/* Deactivate XRES */
  HAL_Delay(10);/* Wait for 10ms after releasing XRES before sending commands */
  /* USER CODE END DSIHOST_Init 0 */

  DSI_PLLInitTypeDef PLLInit = {0};
  DSI_HOST_TimeoutTypeDef HostTimeouts = {0};
  DSI_PHY_TimerTypeDef PhyTimings = {0};
  DSI_LPCmdTypeDef LPCmd = {0};
  DSI_CmdCfgTypeDef CmdCfg = {0};

  hdsi.Instance = DSI;
  hdsi.Init.AutomaticClockLaneControl = DSI_AUTO_CLK_LANE_CTRL_DISABLE;
  hdsi.Init.TXEscapeCkdiv = 4;
  hdsi.Init.NumberOfLanes = DSI_TWO_DATA_LANES;
  PLLInit.PLLNDIV = 119;
  PLLInit.PLLIDF = DSI_PLL_IN_DIV3;
  PLLInit.PLLODF = DSI_PLL_OUT_DIV2;
  if (HAL_DSI_Init(&hdsi, &PLLInit) != HAL_OK)
  {
    Error_Handler();
  }
  HostTimeouts.TimeoutCkdiv = 1;
  HostTimeouts.HighSpeedTransmissionTimeout = 0;
  HostTimeouts.LowPowerReceptionTimeout = 0;
  HostTimeouts.HighSpeedReadTimeout = 0;
  HostTimeouts.LowPowerReadTimeout = 0;
  HostTimeouts.HighSpeedWriteTimeout = 0;
  HostTimeouts.HighSpeedWritePrespMode = DSI_HS_PM_DISABLE;
  HostTimeouts.LowPowerWriteTimeout = 0;
  HostTimeouts.BTATimeout = 0;
  if (HAL_DSI_ConfigHostTimeouts(&hdsi, &HostTimeouts) != HAL_OK)
  {
    Error_Handler();
  }
  PhyTimings.ClockLaneHS2LPTime = 28;
  PhyTimings.ClockLaneLP2HSTime = 33;
  PhyTimings.DataLaneHS2LPTime = 15;
  PhyTimings.DataLaneLP2HSTime = 25;
  PhyTimings.DataLaneMaxReadTime = 0;
  PhyTimings.StopWaitTime = 0;
  if (HAL_DSI_ConfigPhyTimer(&hdsi, &PhyTimings) != HAL_OK)
  {
    Error_Handler();
  }
  if (HAL_DSI_ConfigFlowControl(&hdsi, DSI_FLOW_CONTROL_BTA) != HAL_OK)
  {
    Error_Handler();
  }
  if (HAL_DSI_SetLowPowerRXFilter(&hdsi, 10000) != HAL_OK)
  {
    Error_Handler();
  }
  if (HAL_DSI_ConfigErrorMonitor(&hdsi, HAL_DSI_ERROR_NONE) != HAL_OK)
  {
    Error_Handler();
  }
  LPCmd.LPGenShortWriteNoP = DSI_LP_GSW0P_ENABLE;
  LPCmd.LPGenShortWriteOneP = DSI_LP_GSW1P_ENABLE;
  LPCmd.LPGenShortWriteTwoP = DSI_LP_GSW2P_ENABLE;
  LPCmd.LPGenShortReadNoP = DSI_LP_GSR0P_ENABLE;
  LPCmd.LPGenShortReadOneP = DSI_LP_GSR1P_ENABLE;
  LPCmd.LPGenShortReadTwoP = DSI_LP_GSR2P_ENABLE;
  LPCmd.LPGenLongWrite = DSI_LP_GLW_ENABLE;
  LPCmd.LPDcsShortWriteNoP = DSI_LP_DSW0P_ENABLE;
  LPCmd.LPDcsShortWriteOneP = DSI_LP_DSW1P_ENABLE;
  LPCmd.LPDcsShortReadNoP = DSI_LP_DSR0P_ENABLE;
  LPCmd.LPDcsLongWrite = DSI_LP_DLW_ENABLE;
  LPCmd.LPMaxReadPacket = DSI_LP_MRDP_ENABLE;
  LPCmd.AcknowledgeRequest = DSI_ACKNOWLEDGE_ENABLE;
  if (HAL_DSI_ConfigCommand(&hdsi, &LPCmd) != HAL_OK)
  {
    Error_Handler();
  }
  CmdCfg.VirtualChannelID = 0;
  CmdCfg.ColorCoding = DSI_RGB888;
  CmdCfg.CommandSize = 400;
  CmdCfg.TearingEffectSource = DSI_TE_EXTERNAL;
  CmdCfg.TearingEffectPolarity = DSI_TE_RISING_EDGE;
  CmdCfg.HSPolarity = DSI_HSYNC_ACTIVE_HIGH;
  CmdCfg.VSPolarity = DSI_VSYNC_ACTIVE_HIGH;
  CmdCfg.DEPolarity = DSI_DATA_ENABLE_ACTIVE_HIGH;
  CmdCfg.VSyncPol = DSI_VSYNC_RISING;
  CmdCfg.AutomaticRefresh = DSI_AR_DISABLE;
  CmdCfg.TEAcknowledgeRequest = DSI_TE_ACKNOWLEDGE_ENABLE;
  if (HAL_DSI_ConfigAdaptedCommandMode(&hdsi, &CmdCfg) != HAL_OK)
  {
    Error_Handler();
  }
  if (HAL_DSI_SetGenericVCID(&hdsi, 0) != HAL_OK)
  {
    Error_Handler();
  }

}

static void MX_JPEG_Init(void)
{

  hjpeg.Instance = JPEG;
  if (HAL_JPEG_Init(&hjpeg) != HAL_OK)
  {
    Error_Handler();
  }

}

static void MX_LTDC_Init(void)
{

  LTDC_LayerCfgTypeDef pLayerCfg = {0};

  hltdc.Instance = LTDC;
  hltdc.Init.HSPolarity = LTDC_HSPOLARITY_AH;
  hltdc.Init.VSPolarity = LTDC_VSPOLARITY_AH;
  hltdc.Init.DEPolarity = LTDC_DEPOLARITY_AL;
  hltdc.Init.PCPolarity = LTDC_PCPOLARITY_IPC;
  hltdc.Init.HorizontalSync = 0;
  hltdc.Init.VerticalSync = 0;
  hltdc.Init.AccumulatedHBP = 2;
  hltdc.Init.AccumulatedVBP = 2;
  hltdc.Init.AccumulatedActiveW = 402;
  hltdc.Init.AccumulatedActiveH = 482;
  hltdc.Init.TotalWidth = 403;
  hltdc.Init.TotalHeigh = 483;
  hltdc.Init.Backcolor.Blue = 0;
  hltdc.Init.Backcolor.Green = 0;
  hltdc.Init.Backcolor.Red = 0;
  if (HAL_LTDC_Init(&hltdc) != HAL_OK)
  {
    Error_Handler();
  }
  pLayerCfg.WindowX0 = 0;
  pLayerCfg.WindowX1 = 400;
  pLayerCfg.WindowY0 = 0;
  pLayerCfg.WindowY1 = 480;
  pLayerCfg.PixelFormat = LTDC_PIXEL_FORMAT_RGB888;
  pLayerCfg.Alpha = 255;
  pLayerCfg.Alpha0 = 0;
  pLayerCfg.BlendingFactor1 = LTDC_BLENDING_FACTOR1_PAxCA;
  pLayerCfg.BlendingFactor2 = LTDC_BLENDING_FACTOR2_PAxCA;
  pLayerCfg.FBStartAdress = 0xD0000000;
  pLayerCfg.ImageWidth = 400;
  pLayerCfg.ImageHeight = 480;
  pLayerCfg.Backcolor.Blue = 0;
  pLayerCfg.Backcolor.Green = 0;
  pLayerCfg.Backcolor.Red = 0;
  if (HAL_LTDC_ConfigLayer(&hltdc, &pLayerCfg, 0) != HAL_OK)
  {
    Error_Handler();
  }
  /* USER CODE BEGIN LTDC_Init 2 */

      /* Configure DSI PHY HS2LP and LP2HS timings */

  __HAL_LTDC_DISABLE(&hltdc);
  DSI_LPCmdTypeDef LPCmd;

  HAL_DSI_Start(&hdsi);

  /* Configure the audio driver */
  IOCtx.Address     = 0;
  IOCtx.GetTick     = BSP_GetTick;
  IOCtx.WriteReg    = DSI_IO_Write;
  IOCtx.ReadReg     = DSI_IO_Read;
  OTM8009A_RegisterBusIO(&OTM8009AObj, &IOCtx);

  OTM8009A_Init(&OTM8009AObj ,OTM8009A_FORMAT_RGB888, OTM8009A_ORIENTATION_LANDSCAPE);
  HAL_DSI_ShortWrite(&hdsi, 0, DSI_DCS_SHORT_PKT_WRITE_P1, OTM8009A_CMD_DISPON, 0x00);
  /* Luminosité maximale */
  HAL_DSI_ShortWrite(&hdsi, 0, DSI_DCS_SHORT_PKT_WRITE_P1, OTM8009A_CMD_WRDISBV, 0xFF);
  /* Forcer backlight PJ12 via HAL et registre direct */
  HAL_GPIO_WritePin(GPIOJ, LCD_BL_Pin, GPIO_PIN_SET);
  GPIOJ->BSRR = GPIO_PIN_12; /* force direct via BSRR */
  *((volatile uint32_t*)0x38000300) = 0xBB120002; /* marqueur: LTDC init ok + backlight ON */

  LPCmd.LPGenShortWriteNoP = DSI_LP_GSW0P_DISABLE;
  LPCmd.LPGenShortWriteOneP = DSI_LP_GSW1P_DISABLE;
  LPCmd.LPGenShortWriteTwoP = DSI_LP_GSW2P_DISABLE;
  LPCmd.LPGenShortReadNoP = DSI_LP_GSR0P_DISABLE;
  LPCmd.LPGenShortReadOneP = DSI_LP_GSR1P_DISABLE;
  LPCmd.LPGenShortReadTwoP = DSI_LP_GSR2P_DISABLE;
  LPCmd.LPGenLongWrite = DSI_LP_GLW_DISABLE;
  LPCmd.LPDcsShortWriteNoP = DSI_LP_DSW0P_DISABLE;
  LPCmd.LPDcsShortWriteOneP = DSI_LP_DSW1P_DISABLE;
  LPCmd.LPDcsShortReadNoP = DSI_LP_DSR0P_DISABLE;
  LPCmd.LPDcsLongWrite = DSI_LP_DLW_DISABLE;
  HAL_DSI_ConfigCommand(&hdsi, &LPCmd);

  HAL_LTDC_SetPitch(&hltdc, 800, 0);
  __HAL_LTDC_ENABLE(&hltdc);
  /* USER CODE END LTDC_Init 2 */

}

static void MX_QUADSPI_Init(void)
{

  /* QUADSPI parameter configuration*/
  hqspi.Instance = QUADSPI;
  hqspi.Init.ClockPrescaler = 3;
  hqspi.Init.FifoThreshold = 1;
  hqspi.Init.SampleShifting = QSPI_SAMPLE_SHIFTING_NONE;
  hqspi.Init.FlashSize = 25;
  hqspi.Init.ChipSelectHighTime = QSPI_CS_HIGH_TIME_1_CYCLE;
  hqspi.Init.ClockMode = QSPI_CLOCK_MODE_0;
  hqspi.Init.DualFlash = QSPI_DUALFLASH_ENABLE;
  /* Non-fatal: QSPI failure must not halt the system */
  (void)HAL_QSPI_Init(&hqspi);
  /* USER CODE BEGIN QUADSPI_Init 2 */
  BSP_QSPI_Init_t init ;
  init.InterfaceMode=MT25TL01G_QPI_MODE;
  init.TransferRate= MT25TL01G_DTR_TRANSFER ;
  init.DualFlashMode= MT25TL01G_DUALFLASH_ENABLE;
  /* Non-fatal: QSPI is not required because all assets are in internal FLASH */
  (void)BSP_QSPI_Init(0,&init);
  (void)BSP_QSPI_EnableMemoryMappedMode(0);
  /* USER CODE END QUADSPI_Init 2 */

}

/**
  * Enable MDMA controller clock
  */
static void MX_MDMA_Init(void)
{

  /* MDMA controller clock enable */
  __HAL_RCC_MDMA_CLK_ENABLE();
  /* Local variables */

  /* MDMA interrupt initialization */
  /* MDMA_IRQn interrupt configuration */
  HAL_NVIC_SetPriority(MDMA_IRQn, 5, 0);
  HAL_NVIC_EnableIRQ(MDMA_IRQn);

}

/* FMC initialization function */
void MX_FMC_Init(void)
{

  FMC_SDRAM_TimingTypeDef SdramTiming = {0};

  /* USER CODE BEGIN FMC_Init 1 */
  FMC_Bank1_R->BTCR[0] &= ~FMC_BCRx_MBKEN;
  /* USER CODE END FMC_Init 1 */

  /** Perform the SDRAM1 memory initialization sequence
  */
  hsdram1.Instance = FMC_SDRAM_DEVICE;
  /* hsdram1.Init */
  hsdram1.Init.SDBank = FMC_SDRAM_BANK2;
  hsdram1.Init.ColumnBitsNumber = FMC_SDRAM_COLUMN_BITS_NUM_9;
  hsdram1.Init.RowBitsNumber = FMC_SDRAM_ROW_BITS_NUM_12;
  hsdram1.Init.MemoryDataWidth = FMC_SDRAM_MEM_BUS_WIDTH_32;
  hsdram1.Init.InternalBankNumber = FMC_SDRAM_INTERN_BANKS_NUM_4;
  hsdram1.Init.CASLatency = FMC_SDRAM_CAS_LATENCY_3;
  hsdram1.Init.WriteProtection = FMC_SDRAM_WRITE_PROTECTION_DISABLE;
  hsdram1.Init.SDClockPeriod = FMC_SDRAM_CLOCK_PERIOD_2;
  hsdram1.Init.ReadBurst = FMC_SDRAM_RBURST_ENABLE;
  hsdram1.Init.ReadPipeDelay = FMC_SDRAM_RPIPE_DELAY_0;
  /* SdramTiming */
  SdramTiming.LoadToActiveDelay = 2;
  SdramTiming.ExitSelfRefreshDelay = 7;
  SdramTiming.SelfRefreshTime = 4;
  SdramTiming.RowCycleDelay = 7;
  SdramTiming.WriteRecoveryTime = 3;
  SdramTiming.RPDelay = 2;
  SdramTiming.RCDDelay = 2;

  if (HAL_SDRAM_Init(&hsdram1, &SdramTiming) != HAL_OK)
  {
    Error_Handler( );
  }

  /* USER CODE BEGIN FMC_Init 2 */
  BSP_SDRAM_DeInit(0);
  if(BSP_SDRAM_Init(0) != BSP_ERROR_NONE)
  {
    Error_Handler();
  }
  /* USER CODE END FMC_Init 2 */
}

static void MX_GPIO_Init(void)
{
  GPIO_InitTypeDef GPIO_InitStruct = {0};

  /* GPIO Ports Clock Enable */
  __HAL_RCC_GPIOI_CLK_ENABLE();
  __HAL_RCC_GPIOB_CLK_ENABLE();
  __HAL_RCC_GPIOG_CLK_ENABLE();
  __HAL_RCC_GPIOE_CLK_ENABLE();
  __HAL_RCC_GPIOH_CLK_ENABLE();
  __HAL_RCC_GPIOC_CLK_ENABLE();
  __HAL_RCC_GPIOJ_CLK_ENABLE();
  __HAL_RCC_GPIOD_CLK_ENABLE();
  __HAL_RCC_GPIOA_CLK_ENABLE();
  __HAL_RCC_GPIOF_CLK_ENABLE();

  /*Configure GPIO pin Output Level */
  HAL_GPIO_WritePin(GPIOJ, LCD_BL_Pin|FRAME_RATE_Pin|RENDER_TIME_Pin|VSYNC_FREQ_Pin, GPIO_PIN_RESET);

  /*Configure GPIO pin Output Level */
  HAL_GPIO_WritePin(LCD_RESET_GPIO_Port, LCD_RESET_Pin, GPIO_PIN_RESET);

  /*Configure GPIO pin Output Level */
  HAL_GPIO_WritePin(MCU_ACTIVE_GPIO_Port, MCU_ACTIVE_Pin, GPIO_PIN_RESET);

  /*Configure GPIO pins : LCD_BL_Pin FRAME_RATE_Pin RENDER_TIME_Pin VSYNC_FREQ_Pin */
  GPIO_InitStruct.Pin = LCD_BL_Pin|FRAME_RATE_Pin|RENDER_TIME_Pin|VSYNC_FREQ_Pin;
  GPIO_InitStruct.Mode = GPIO_MODE_OUTPUT_PP;
  GPIO_InitStruct.Pull = GPIO_NOPULL;
  GPIO_InitStruct.Speed = GPIO_SPEED_FREQ_VERY_HIGH;
  HAL_GPIO_Init(GPIOJ, &GPIO_InitStruct);

  /* === FORCE DIRECT: PJ12 en sortie push-pull via registres bruts ===
   * GPIOJ MODER base = 0x58026000
   * PJ12 = bits [25:24] → valeur 01 = output
   * On force aussi PJ0,PJ1,PJ2,PJ3,PJ4 (FRAME_RATE,RENDER_TIME,VSYNC_FREQ)
   * et PJ12 (LCD_BL) en mode output direct pour contourner tout problème de domaine */
  __HAL_RCC_GPIOJ_CLK_ENABLE(); /* S'assurer que la clock est active */
  /* Configurer PJ12 en output PP via MODER : bits 25:24 = 01 */
  GPIOJ->MODER &= ~(0x3U << (12 * 2));  /* clear bits 25:24 */
  GPIOJ->MODER |=  (0x1U << (12 * 2));  /* set output mode */
  /* Allumer immédiatement PJ12 via BSRR (set bit 12) */
  GPIOJ->BSRR = GPIO_PIN_12;
  /* Marquer dans SRAM4 que la GPIO est initialisée */
  *((volatile uint32_t*)0x38000300) = 0xBB120001;

  /*Configure GPIO pin : PA8 */
  GPIO_InitStruct.Pin = GPIO_PIN_8;
  GPIO_InitStruct.Mode = GPIO_MODE_AF_PP;
  GPIO_InitStruct.Pull = GPIO_NOPULL;
  GPIO_InitStruct.Speed = GPIO_SPEED_FREQ_LOW;
  GPIO_InitStruct.Alternate = GPIO_AF0_MCO;
  HAL_GPIO_Init(GPIOA, &GPIO_InitStruct);

  /* Configure FDCAN1 GPIO : PA11(RX) et PA12(TX) en AF9 avec PULLUP */
  GPIO_InitStruct.Pin = GPIO_PIN_11 | GPIO_PIN_12;
  GPIO_InitStruct.Mode = GPIO_MODE_AF_PP;
  GPIO_InitStruct.Pull = GPIO_PULLUP;
  GPIO_InitStruct.Speed = GPIO_SPEED_FREQ_VERY_HIGH;
  GPIO_InitStruct.Alternate = GPIO_AF9_FDCAN1;
  HAL_GPIO_Init(GPIOA, &GPIO_InitStruct);

  /*Configure GPIO pin : LCD_RESET_Pin */
  GPIO_InitStruct.Pin = LCD_RESET_Pin;
  GPIO_InitStruct.Mode = GPIO_MODE_OUTPUT_PP;
  GPIO_InitStruct.Pull = GPIO_PULLUP;
  GPIO_InitStruct.Speed = GPIO_SPEED_FREQ_VERY_HIGH;
  HAL_GPIO_Init(LCD_RESET_GPIO_Port, &GPIO_InitStruct);

  /*Configure GPIO pin : MCU_ACTIVE_Pin */
  GPIO_InitStruct.Pin = MCU_ACTIVE_Pin;
  GPIO_InitStruct.Mode = GPIO_MODE_OUTPUT_PP;
  GPIO_InitStruct.Pull = GPIO_NOPULL;
  GPIO_InitStruct.Speed = GPIO_SPEED_FREQ_VERY_HIGH;
  HAL_GPIO_Init(MCU_ACTIVE_GPIO_Port, &GPIO_InitStruct);

  /* USER CODE BEGIN MX_GPIO_Init_2 */
  /* LCD Hardware Reset: Active LOW */
  HAL_GPIO_WritePin(LCD_RESET_GPIO_Port, LCD_RESET_Pin, GPIO_PIN_RESET);
  HAL_Delay(20);
  HAL_GPIO_WritePin(LCD_RESET_GPIO_Port, LCD_RESET_Pin, GPIO_PIN_SET);
  HAL_Delay(50);

  /* Turn on LCD Backlight */
  HAL_GPIO_WritePin(LCD_BL_GPIO_Port, LCD_BL_Pin, GPIO_PIN_SET);
  /* USER CODE END MX_GPIO_Init_2 */
}

/* USER CODE BEGIN Header_TouchGFX_Task */
/**
  * @brief  TouchGFX_Task is implemented in app_touchgfx.c
  */
/* USER CODE END Header_TouchGFX_Task */

 /* MPU Configuration */

void MPU_Config(void)
{
  MPU_Region_InitTypeDef MPU_InitStruct = {0};

  /* Disables the MPU */
  HAL_MPU_Disable();

  /** Initializes and configures the Region and the memory to be protected
  */
  MPU_InitStruct.Enable = MPU_REGION_ENABLE;
  MPU_InitStruct.Number = MPU_REGION_NUMBER0;
  MPU_InitStruct.BaseAddress = 0x90000000;
  MPU_InitStruct.Size = MPU_REGION_SIZE_256MB;
  MPU_InitStruct.SubRegionDisable = 0x0;
  MPU_InitStruct.TypeExtField = MPU_TEX_LEVEL0;
  MPU_InitStruct.AccessPermission = MPU_REGION_FULL_ACCESS;
  MPU_InitStruct.DisableExec = MPU_INSTRUCTION_ACCESS_DISABLE;
  MPU_InitStruct.IsShareable = MPU_ACCESS_NOT_SHAREABLE;
  MPU_InitStruct.IsCacheable = MPU_ACCESS_NOT_CACHEABLE;
  MPU_InitStruct.IsBufferable = MPU_ACCESS_NOT_BUFFERABLE;

  HAL_MPU_ConfigRegion(&MPU_InitStruct);

  /** Initializes and configures the Region and the memory to be protected
  */
  MPU_InitStruct.Number = MPU_REGION_NUMBER1;
  MPU_InitStruct.Size = MPU_REGION_SIZE_128MB;

  HAL_MPU_ConfigRegion(&MPU_InitStruct);

  /** Initializes and configures the Region and the memory to be protected
  */
  MPU_InitStruct.Number = MPU_REGION_NUMBER2;
  MPU_InitStruct.BaseAddress = 0xD0000000;
  MPU_InitStruct.Size = MPU_REGION_SIZE_32MB;
  MPU_InitStruct.IsCacheable = MPU_ACCESS_CACHEABLE;

  HAL_MPU_ConfigRegion(&MPU_InitStruct);

  /** Initializes and configures the Region and the memory to be protected
  */
  MPU_InitStruct.Number = MPU_REGION_NUMBER3;
  MPU_InitStruct.BaseAddress = 0x24000000;
  MPU_InitStruct.Size = MPU_REGION_SIZE_512KB;
  MPU_InitStruct.DisableExec = MPU_INSTRUCTION_ACCESS_ENABLE;

  HAL_MPU_ConfigRegion(&MPU_InitStruct);

  /** Initializes and configures the Region and the memory to be protected
  */
  MPU_InitStruct.Number = MPU_REGION_NUMBER4;
  MPU_InitStruct.BaseAddress = 0x10000000;
  MPU_InitStruct.Size = MPU_REGION_SIZE_256KB;

  HAL_MPU_ConfigRegion(&MPU_InitStruct);

  /** Initializes and configures the Region and the memory to be protected
  */
  MPU_InitStruct.Number = MPU_REGION_NUMBER5;
  MPU_InitStruct.BaseAddress = 0x10040000;
  MPU_InitStruct.Size = MPU_REGION_SIZE_32KB;
  MPU_InitStruct.DisableExec = MPU_INSTRUCTION_ACCESS_DISABLE;

  HAL_MPU_ConfigRegion(&MPU_InitStruct);

  /* === REGION 6 : SRAM4 (0x38000000, 64 KB) — SHARED CM4/CM7 — NON-CACHEABLE ===
   * CRITICAL: Sans cette région, le D-Cache du CM7 lit des valeurs périmées.
   * Le CM4 écrit dans SRAM4 mais le CM7 voit l'ancienne valeur en cache.
   * TEX=0, C=0, B=0 → Strongly Ordered (aucun cache, aucun reorder) */
  MPU_InitStruct.Number         = MPU_REGION_NUMBER6;
  MPU_InitStruct.BaseAddress    = 0x38000000;  /* SRAM4 base */
  MPU_InitStruct.Size           = MPU_REGION_SIZE_64KB;
  MPU_InitStruct.SubRegionDisable = 0x0;
  MPU_InitStruct.TypeExtField   = MPU_TEX_LEVEL0;
  MPU_InitStruct.AccessPermission = MPU_REGION_FULL_ACCESS;
  MPU_InitStruct.DisableExec    = MPU_INSTRUCTION_ACCESS_DISABLE;
  MPU_InitStruct.IsShareable    = MPU_ACCESS_SHAREABLE;
  MPU_InitStruct.IsCacheable    = MPU_ACCESS_NOT_CACHEABLE;
  MPU_InitStruct.IsBufferable   = MPU_ACCESS_NOT_BUFFERABLE;

  HAL_MPU_ConfigRegion(&MPU_InitStruct);

  /* Enables the MPU */
  HAL_MPU_Enable(MPU_PRIVILEGED_DEFAULT);

}

void HAL_TIM_PeriodElapsedCallback(TIM_HandleTypeDef *htim)
{
  if (htim->Instance == TIM6)
  {
    HAL_IncTick();
  }
}

void Error_Handler(void)
{
  /* USER CODE BEGIN Error_Handler_Debug */
  /* Non-fatal: peripheral init failures must not halt the system.
     CAN transceiver signals on PB8/PB9 can disturb QSPI/FMC at boot.
     Just re-enable IRQ and return so initialization continues. */
  __enable_irq();
  /* USER CODE END Error_Handler_Debug */
}
